VERSION 5.8 ;
BUSBITCHARS "[]" ;

# A tall L-shaped hard macro: 70um high against a 95.2um core, so a core
# strap crossing it has to be cut rather than routed around.
#
# As in polygon_macro.lef the real outline is the OVERLAP-layer polygon and
# SIZE is only its bounding box.  Unlike polygon_macro.lef this one blocks
# metal1 through metal5 over its body and carries its supply pins on
# metal6, which is what a large block does: a core metal4 strap over the
# body has nowhere to go, while one over the notch is unobstructed.
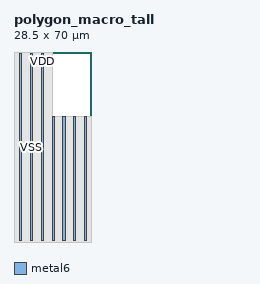
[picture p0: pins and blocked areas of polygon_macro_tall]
MACRO polygon_macro_tall
  CLASS BLOCK ;
  FOREIGN polygon_macro_tall 0 0 ;
  ORIGIN 0 0 ;
  SYMMETRY X Y R90 ;
  SIZE 28.500 BY 70.000 ;
  PIN VDD
    DIRECTION INOUT ;
    USE POWER ;
    PORT
      LAYER metal6 ;
      RECT 2.000 0.700 2.800 69.300 ;
      RECT 10.000 0.700 10.800 69.300 ;
      RECT 18.000 0.700 18.800 46.200 ;
      RECT 26.000 0.700 26.800 46.200 ;
    END
  END VDD
  PIN VSS
    DIRECTION INOUT ;
    USE GROUND ;
    PORT
      LAYER metal6 ;
      RECT 6.000 0.700 6.800 69.300 ;
      RECT 14.000 0.700 14.800 46.200 ;
      RECT 22.000 0.700 22.800 46.200 ;
    END
  END VSS
  OBS
    LAYER metal1 ;
      POLYGON 0.000 0.000 28.500 0.000 28.500 46.200 14.250 46.200 14.250 70.000 0.000 70.000 ;
    LAYER metal2 ;
      POLYGON 0.000 0.000 28.500 0.000 28.500 46.200 14.250 46.200 14.250 70.000 0.000 70.000 ;
    LAYER metal3 ;
      POLYGON 0.000 0.000 28.500 0.000 28.500 46.200 14.250 46.200 14.250 70.000 0.000 70.000 ;
    LAYER metal4 ;
      POLYGON 0.000 0.000 28.500 0.000 28.500 46.200 14.250 46.200 14.250 70.000 0.000 70.000 ;
    LAYER metal5 ;
      POLYGON 0.000 0.000 28.500 0.000 28.500 46.200 14.250 46.200 14.250 70.000 0.000 70.000 ;
    LAYER OVERLAP ;
      POLYGON 0.000 0.000 28.500 0.000 28.500 46.200 14.250 46.200 14.250 70.000 0.000 70.000 ;
  END
END polygon_macro_tall

END LIBRARY
